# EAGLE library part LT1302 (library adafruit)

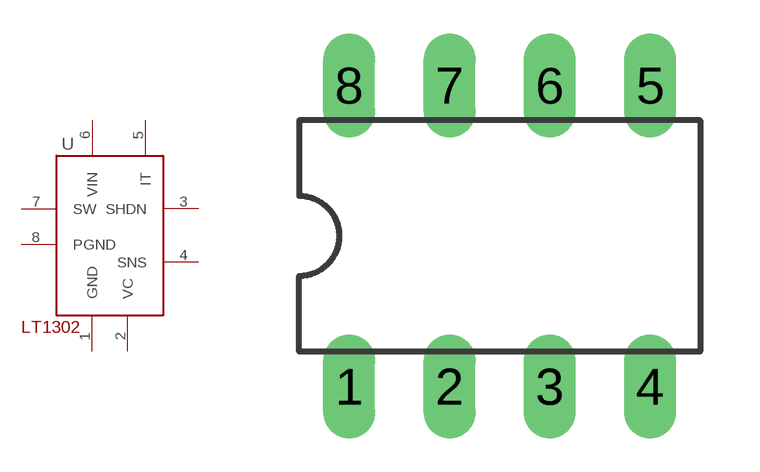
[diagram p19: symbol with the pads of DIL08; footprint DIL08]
Designator prefix -

## LT1302  [DIL08]
1  GND  in
2  VC  pas
3  SHDN  in
4  SNS  pas
5  IT  in
6  VIN  in
7  SW  in
8  PGND  in

## Footprint DIL08 (pad centres in mm)
Dual In Line Package
drill 0.813 long: 1 -3.81,-3.81; 2 -1.27,-3.81; 3 1.27,-3.81; 4 3.81,-3.81; 5 3.81,3.81; 6 1.27,3.81; 7 -1.27,3.81; 8 -3.81,3.81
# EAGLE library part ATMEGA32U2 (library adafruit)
ATmega32u2 Pin compatible with the atmega8u2, atmega16u2 and atmega32u2 8, 16 or 32 K flash, 1K RAM, 512b EEPROM 8 bit and 16 bit timer (5 PWM total) UART, SPI (no I2C!) USB with 4 endpoints, LUFA compatible 22 I/O lines, analog comparator (no ADC!) Comes with DFU bootloader burned in!

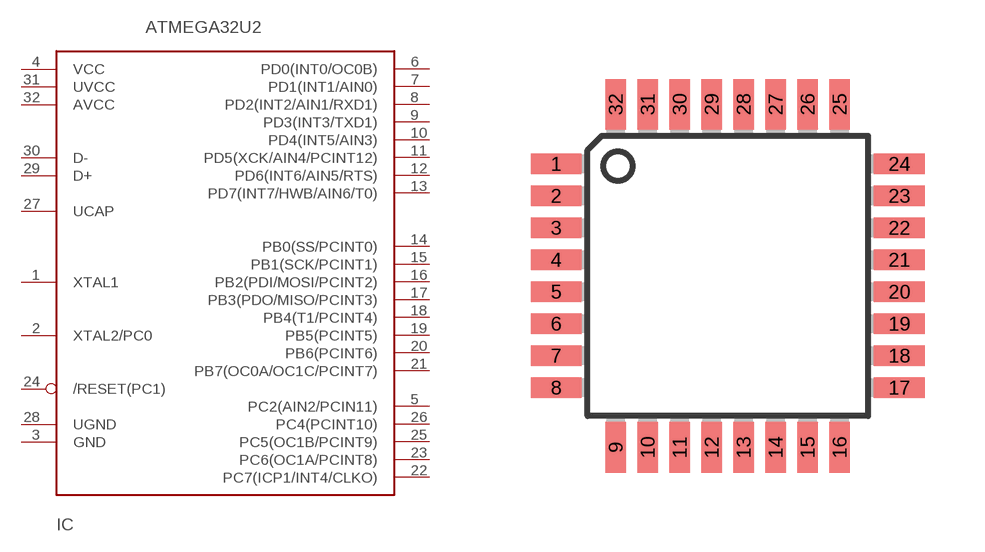
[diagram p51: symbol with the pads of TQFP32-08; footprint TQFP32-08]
Designator prefix IC

## ATMEGA32U2-TQFP  [TQFP32-08]
1  XTAL1
2  XTAL2/PC0
3  GND
4  VCC
5  PC2(AIN2/PCIN11)
6  PD0(INT0/OC0B)
7  PD1(INT1/AIN0)
8  PD2(INT2/AIN1/RXD1)
9  PD3(INT3/TXD1)
10  PD4(INT5/AIN3)
11  PD5(XCK/AIN4/PCINT12)
12  PD6(INT6/AIN5/RTS)
13  PD7(INT7/HWB/AIN6/T0)
14  PB0(SS/PCINT0)
15  PB1(SCK/PCINT1)
16  PB2(PDI/MOSI/PCINT2)
17  PB3(PDO/MISO/PCINT3)
18  PB4(T1/PCINT4)
19  PB5(PCINT5)
20  PB6(PCINT6)
21  PB7(OC0A/OC1C/PCINT7)
22  PC7(ICP1/INT4/CLKO)
23  PC6(OC1A/PCINT8)
24  /RESET(PC1)
25  PC5(OC1B/PCINT9)
26  PC4(PCINT10)
27  UCAP
28  UGND
29  D+
30  D-
31  UVCC
32  AVCC

## Footprint TQFP32-08 (pad centres in mm)
Thin Plasic Quad Flat Package Grid 0.8 mm
smd 1.27 x 0.508: 1 -4.293,2.8; 2 -4.293,2; 3 -4.293,1.2; 4 -4.293,0.4; 5 -4.293,-0.4; 6 -4.293,-1.2; 7 -4.293,-2; 8 -4.293,-2.8; 17 4.293,-2.8; 18 4.293,-2; 19 4.293,-1.2; 20 4.293,-0.4; 21 4.293,0.4; 22 4.293,1.2; 23 4.293,2; 24 4.293,2.8
smd 0.508 x 1.27: 9 -2.8,-4.293; 10 -2,-4.293; 11 -1.2,-4.293; 12 -0.4,-4.293; 13 0.4,-4.293; 14 1.2,-4.293; 15 2,-4.293; 16 2.8,-4.293; 25 2.8,4.293; 26 2,4.293; 27 1.2,4.293; 28 0.4,4.293; 29 -0.4,4.293; 30 -1.2,4.293; 31 -2,4.293; 32 -2.8,4.293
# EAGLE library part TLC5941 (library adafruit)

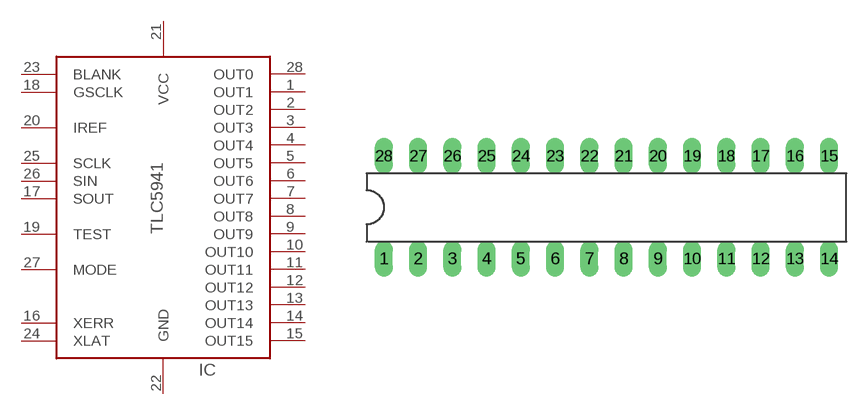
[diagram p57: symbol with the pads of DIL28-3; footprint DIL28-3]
Designator prefix IC

## TLC5941NT  [DIL28-3]
1  OUT1  out
2  OUT2  out
3  OUT3  out
4  OUT4  out
5  OUT5  out
6  OUT6  out
7  OUT7  out
8  OUT8  out
9  OUT9  out
10  OUT10  out
11  OUT11  out
12  OUT12  out
13  OUT13  out
14  OUT14  out
15  OUT15  out
16  XERR  out
17  SOUT  out
18  GSCLK  in
19  TEST  in
20  IREF
21  VCC  pwr
22  GND  pwr
23  BLANK  in
24  XLAT  in
25  SCLK  in
26  SIN  in
27  MODE  in
28  OUT0  out

## Footprint DIL28-3 (pad centres in mm)
Dual In Line package type P
drill 0.813 long: 1 -16.51,-3.81; 2 -13.97,-3.81; 3 -11.43,-3.81; 4 -8.89,-3.81; 5 -6.35,-3.81; 6 -3.81,-3.81; 7 -1.27,-3.81; 8 1.27,-3.81; 9 3.81,-3.81; 10 6.35,-3.81; 11 8.89,-3.81; 12 11.43,-3.81; 13 13.97,-3.81; 14 16.51,-3.81; 15 16.51,3.81; 16 13.97,3.81; 17 11.43,3.81; 18 8.89,3.81; 19 6.35,3.81; 20 3.81,3.81; 21 1.27,3.81; 22 -1.27,3.81; 23 -3.81,3.81; 24 -6.35,3.81; 25 -8.89,3.81; 26 -11.43,3.81; 27 -13.97,3.81; 28 -16.51,3.81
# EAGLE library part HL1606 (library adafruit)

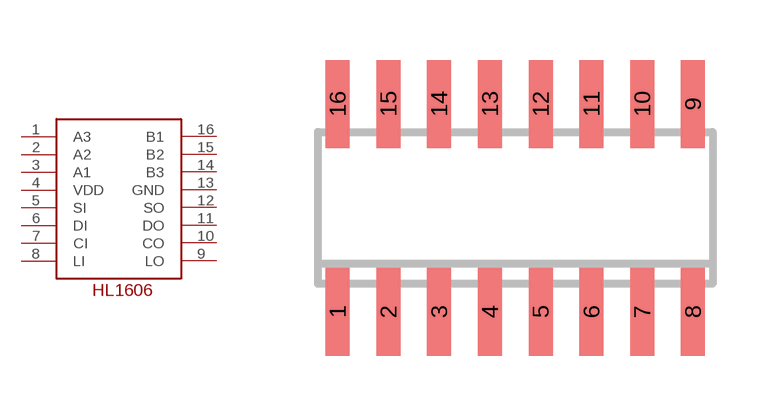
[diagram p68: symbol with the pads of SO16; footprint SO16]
Designator prefix -

## HL1606  [SO16]
1  A3  out
2  A2  out
3  A1  out
4  VDD  pwr
5  SI  in
6  DI  in
7  CI  in
8  LI  in
9  LO  out
10  CO  out
11  DO  out
12  SO  out
13  GND  pwr
14  B3  out
15  B2  out
16  B1  out

## Footprint SO16 (pad centres in mm)
SMALL OUTLINE INTEGRATED CIRCUIT body 3.9 mm/JEDEC MS-012AC
smd 0.6 x 2.2: 1 -4.445,-2.6; 2 -3.175,-2.6; 3 -1.905,-2.6; 4 -0.635,-2.6; 5 0.635,-2.6; 6 1.905,-2.6; 7 3.175,-2.6; 8 4.445,-2.6; 9 4.445,2.6; 10 3.175,2.6; 11 1.905,2.6; 12 0.635,2.6; 13 -0.635,2.6; 14 -1.905,2.6; 15 -3.175,2.6; 16 -4.445,2.6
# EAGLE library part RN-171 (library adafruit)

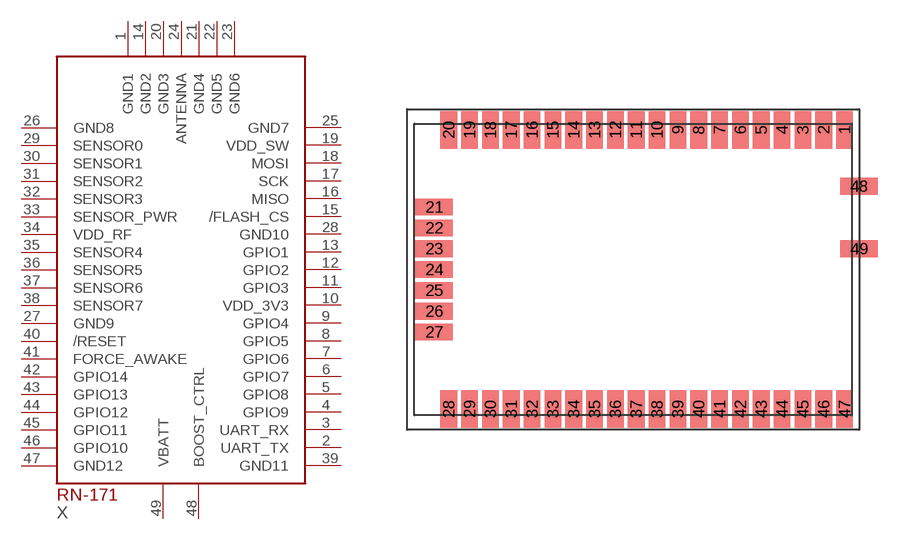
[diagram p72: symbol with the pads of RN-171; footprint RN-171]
Designator prefix X

## RN-171  [RN-171]
1  GND1  pwr
2  UART_TX  out
3  UART_RX  in
4  GPIO9
5  GPIO8
6  GPIO7
7  GPIO6
8  GPIO5
9  GPIO4
10  VDD_3V3  pwr
11  GPIO3
12  GPIO2
13  GPIO1
14  GND2  pwr
15  /FLASH_CS  in
16  MISO  out
17  SCK  in
18  MOSI  in
19  VDD_SW  nc
20  GND3  pwr
21  GND4  pwr
22  GND5  pwr
23  GND6  pwr
24  ANTENNA  out
25  GND7  pwr
26  GND8  pwr
27  GND9  pwr
28  GND10  pwr
29  SENSOR0  in
30  SENSOR1  in
31  SENSOR2  in
32  SENSOR3  in
33  SENSOR_PWR  pwr
34  VDD_RF  pwr
35  SENSOR4  in
36  SENSOR5  in
37  SENSOR6  in
38  SENSOR7  in
39  GND11  pwr
40  /RESET  in
41  FORCE_AWAKE  in
42  GPIO14  nc
43  GPIO13
44  GPIO12
45  GPIO11
46  GPIO10
47  GND12  pwr
48  BOOST_CTRL  out
49  VBATT  in

## Footprint RN-171 (pad centres in mm)
smd 1.016 x 2.286: 1 12.89,8.509; 2 11.62,8.509; 3 10.351,8.509; 4 9.081,8.509; 5 7.811,8.509; 6 6.54,8.509; 7 5.271,8.509; 8 4,8.509; 9 2.731,8.509; 10 1.46,8.509; 11 0.191,8.509; 12 -1.079,8.509; 13 -2.349,8.509; 14 -3.619,8.509; 15 -4.889,8.509; 16 -6.16,8.509; 17 -7.429,8.509; 18 -8.7,8.509; 19 -9.97,8.509; 20 -11.239,8.509; 28 -11.239,-8.509; 29 -9.97,-8.509; 30 -8.7,-8.509; 31 -7.429,-8.509; 32 -6.16,-8.509; 33 -4.889,-8.509; 34 -3.619,-8.509; 35 -2.349,-8.509; 36 -1.079,-8.509; 37 0.191,-8.509; 38 1.46,-8.509; 39 2.731,-8.509; 40 4,-8.509; 41 5.271,-8.509; 42 6.54,-8.509; 43 7.811,-8.509; 44 9.081,-8.509; 45 10.351,-8.509; 46 11.62,-8.509; 47 12.89,-8.509
smd 2.286 x 1.016: 21 -12.129,3.81; 22 -12.129,2.54; 23 -12.129,1.27; 24 -12.129,0; 25 -12.129,-1.27; 26 -12.129,-2.54; 27 -12.129,-3.81; 48 13.78,5.08; 49 13.78,1.27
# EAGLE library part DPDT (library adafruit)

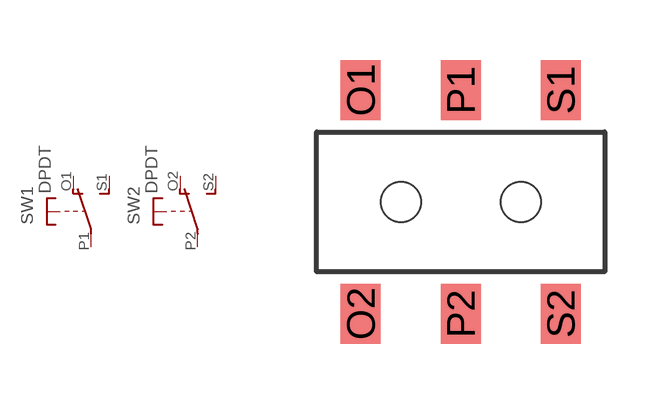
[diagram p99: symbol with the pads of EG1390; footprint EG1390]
Designator prefix SW; gates 1=TSU 2=TSU

## DPDT-EG1390  [EG1390]
O1  1:O  pas
O2  2:O  pas
P1  1:P  pas
P2  2:P  pas
S1  1:S  pas
S2  2:S  pas

## Footprint EG1390 (pad centres in mm)
smd 1 x 1.5: O1 -2.5,2.8; O2 -2.5,-2.8; P1 0,2.8; P2 0,-2.8; S1 2.5,2.8; S2 2.5,-2.8
hole 1 at 1.5,0
hole 1 at -1.5,0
